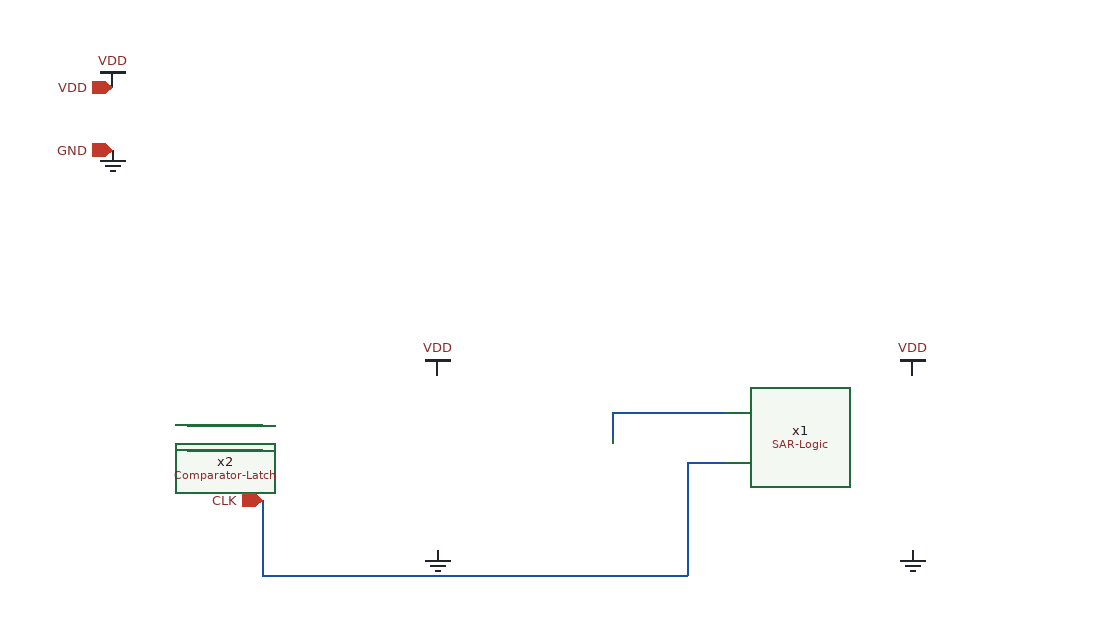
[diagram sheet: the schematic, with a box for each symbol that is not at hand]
v {xschem version=3.4.4 file_version=1.2
}
G {}
K {}
V {}
S {}
E {}
N -520 20 -520 80 {}
N -520 80 -180 80 {}
N -180 -10 -180 80 {}
N -180 -10 -150 -10 {}
N -240 -50 -240 -30 {}
N -240 -50 -150 -50 {}
N -580 -20 -520 -20 {}
N -580 -40 -520 -40 {}
C {SAR-Logic.sym} 0 -10 0 0 {name=x1}
C {Comparator-Latch.sym} -380 -10 0 0 {name=x2}
C {gnd.sym} -640 -260 0 0 {name=l27 lab=GND}
C {vdd.sym} -640 -310 0 0 {name=l28 lab=VDD}
C {ipin.sym} -640 -260 0 0 {name=p3 lab=GND}
C {ipin.sym} -640 -310 0 0 {name=p5 lab=VDD}
C {vdd.sym} -380 -80 0 0 {name=l1 lab=VDD}
C {vdd.sym} 0 -80 0 0 {name=l2 lab=VDD}
C {gnd.sym} -380 60 0 0 {name=l3 lab=GND}
C {gnd.sym} 0 60 0 0 {name=l4 lab=GND}
C {ipin.sym} -520 20 0 0 {name=p1 lab=CLK}
